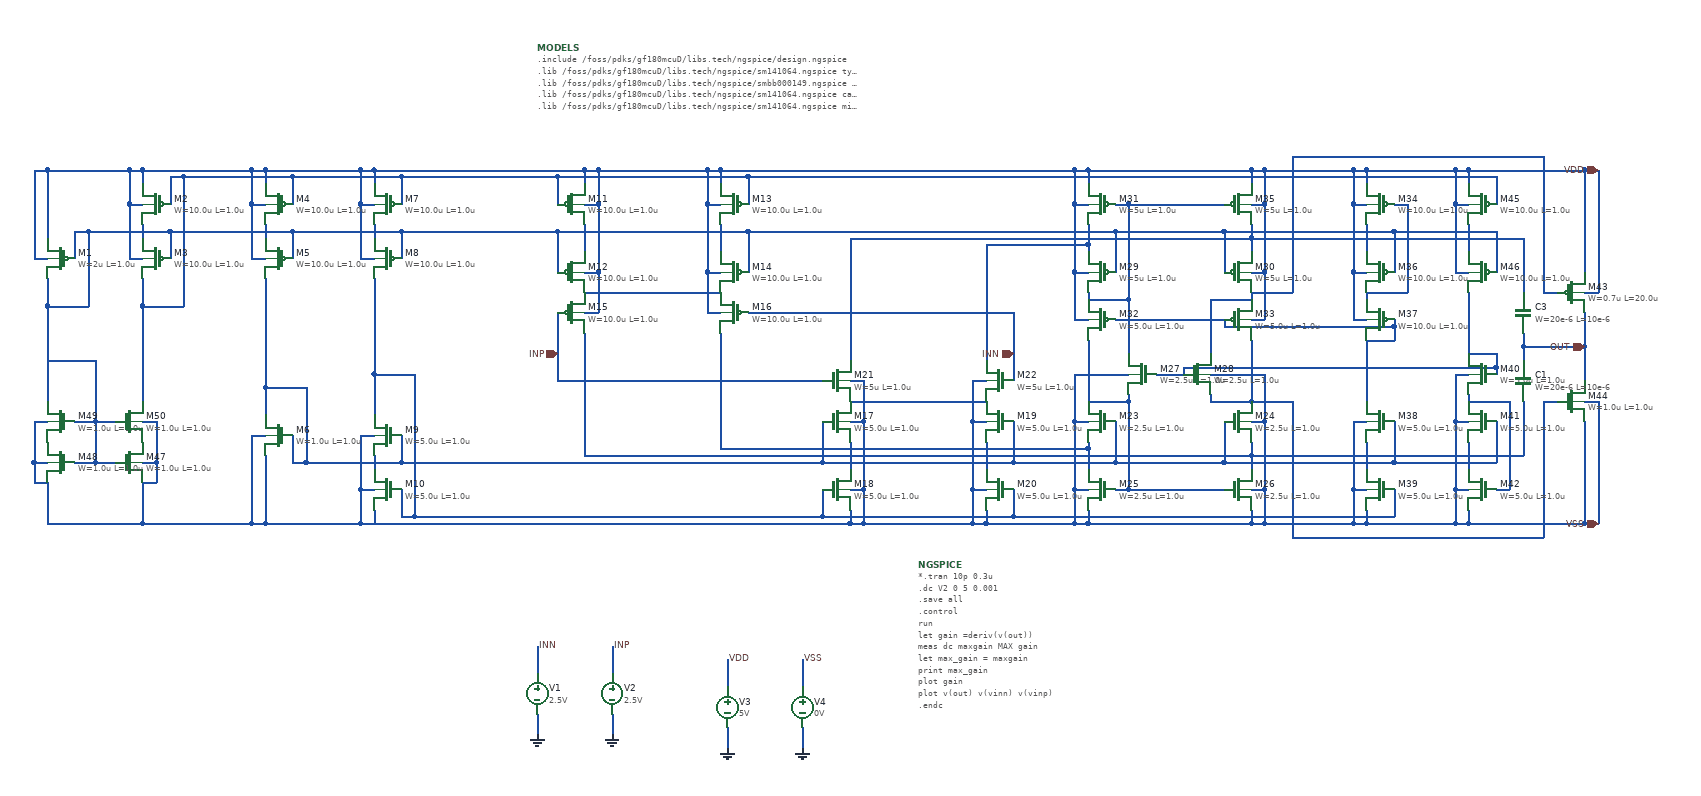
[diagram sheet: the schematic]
v {xschem version=3.4.8RC file_version=1.3}
G {}
K {}
V {}
S {}
F {}
E {}
P 4 1 -1230 -70 {}
N -1010 -230 -990 -230 {
lab=VDD}
N -830 -230 -810 -230 {
lab=VDD}
N -1010 -440 -1010 -420 {
lab=VDD}
N -1010 -390 -990 -390 {
lab=VDD}
N -1050 -430 -1050 -390 {
lab=#net1}
N -290 30 -290 80 {
lab=VSS}
N -290 30 -270 30 {
lab=VSS}
N -270 60 -270 80 {
lab=VSS}
N -270 -440 -270 -420 {
lab=VDD}
N -290 -390 -270 -390 {
lab=VDD}
N -30 -440 -30 -420 {
lab=VDD}
N -30 -390 -10 -390 {
lab=VDD}
N -10 -390 -10 -290 {
lab=VDD}
N -30 30 -10 30 {
lab=VSS}
N -30 60 -30 80 {
lab=VSS}
N -1050 -230 -1050 -130 {
lab=INP}
N -440 -130 -420 -130 {
lab=VSS}
N -620 -70 -600 -70 {
lab=VSS}
N -600 30 -600 80 {
lab=VSS}
N -620 30 -600 30 {
lab=VSS}
N -620 -40 -620 0 {
lab=#net2}
N -620 60 -620 80 {
lab=VSS}
N -660 30 -660 70 {
lab=#net3}
N -660 -70 -660 -10 {
lab=#net4}
N -1010 -290 -990 -290 {
lab=VDD}
N -1010 -360 -1010 -320 {
lab=#net5}
N -1050 -350 -1050 -290 {
lab=#net6}
N -290 -390 -290 -290 {
lab=VDD}
N -290 -290 -270 -290 {
lab=VDD}
N -270 -330 -270 -320 {
lab=#net7}
N -290 -70 -270 -70 {
lab=VSS}
N -290 -70 -290 30 {
lab=VSS}
N -270 -30 -270 0 {
lab=#net8}
N -30 -20 -30 0 {
lab=#net9}
N -30 -70 -10 -70 {
lab=VSS}
N -770 -230 -380 -230 {
lab=INN}
N -380 -230 -380 -130 {
lab=INN}
N -30 -290 -10 -290 {
lab=VDD}
N -30 -340 -30 -320 {
lab=#net10}
N -1010 -260 -810 -260 {
lab=#net11}
N -1050 -130 -660 -130 {
lab=INP}
N -620 -100 -420 -100 {
lab=#net12}
N -270 -260 -270 -250 {
lab=#net13}
N -290 -220 -270 -220 {
lab=VDD}
N -290 -290 -290 -220 {
lab=VDD}
N -210 30 -70 30 {
lab=#net14}
N -10 30 -10 80 {
lab=VSS}
N -170 -140 -130 -140 {
lab=#net15}
N -30 -220 -10 -220 {
lab=VDD}
N -10 -290 -10 -220 {
lab=VDD}
N -30 -260 -30 -250 {
lab=#net16}
N -90 -140 -10 -140 {
lab=VSS}
N -10 -140 -10 -70 {
lab=VSS}
N 460 -180 460 -130 {
lab=OUT}
N 460 -260 480 -260 {
lab=VDD}
N 480 -440 480 -260 {
lab=VDD}
N 140 -440 270 -440 {
lab=VDD}
N 460 -100 480 -100 {
lab=VSS}
N 480 -100 480 80 {
lab=VSS}
N 460 -70 460 80 {
lab=VSS}
N 460 -440 460 -290 {
lab=VDD}
N 120 -390 140 -390 {
lab=VDD}
N 120 -440 120 -390 {
lab=VDD}
N 140 -440 140 -420 {
lab=VDD}
N 140 -360 140 -320 {
lab=#net17}
N 120 -290 140 -290 {
lab=VDD}
N 120 -390 120 -290 {
lab=VDD}
N 140 -260 140 -250 {
lab=#net18}
N 120 -220 140 -220 {
lab=VDD}
N 120 -290 120 -220 {
lab=VDD}
N 120 -70 140 -70 {
lab=VSS}
N 120 30 120 80 {
lab=VSS}
N 120 30 140 30 {
lab=VSS}
N 140 -40 140 0 {
lab=#net19}
N 140 60 140 80 {
lab=VSS}
N 180 30 180 70 {
lab=#net3}
N 180 -70 180 -10 {
lab=#net4}
N 270 -390 290 -390 {
lab=VDD}
N 270 -440 270 -390 {
lab=VDD}
N 290 -440 290 -420 {
lab=VDD}
N 290 -360 290 -320 {
lab=#net20}
N 270 -290 290 -290 {
lab=VDD}
N 270 -390 270 -290 {
lab=VDD}
N 270 -70 290 -70 {
lab=VSS}
N 270 30 270 80 {
lab=VSS}
N 270 30 290 30 {
lab=VSS}
N 290 -40 290 0 {
lab=#net21}
N 290 60 290 80 {
lab=VSS}
N 290 -110 290 -100 {
lab=#net22}
N 270 -140 290 -140 {
lab=VSS}
N 270 -140 270 -70 {
lab=VSS}
N 290 -440 460 -440 {
lab=VDD}
N -810 -440 -810 -420 {
lab=VDD}
N -830 -390 -810 -390 {
lab=VDD}
N -770 -430 -770 -390 {
lab=#net1}
N -830 -290 -810 -290 {
lab=VDD}
N -810 -360 -810 -320 {
lab=#net23}
N -770 -350 -770 -290 {
lab=#net6}
N -440 -70 -420 -70 {
lab=VSS}
N -440 30 -420 30 {
lab=VSS}
N -420 -40 -420 0 {
lab=#net24}
N -420 60 -420 80 {
lab=VSS}
N -380 30 -380 70 {
lab=#net3}
N -380 -70 -380 -10 {
lab=#net4}
N -620 -130 -600 -130 {
lab=VSS}
N 180 -350 180 -290 {
lab=#net6}
N 180 -390 200 -390 {
lab=#net18}
N 200 -390 200 -260 {
lab=#net18}
N 140 -260 200 -260 {
lab=#net18}
N 180 -210 180 -190 {
lab=#net25}
N 140 -190 180 -190 {
lab=#net25}
N 140 -190 140 -100 {
lab=#net25}
N 330 -430 330 -390 {
lab=#net1}
N 330 -350 330 -290 {
lab=#net6}
N -70 -10 180 -10 {
lab=#net4}
N 330 -70 330 -10 {
lab=#net4}
N 330 30 350 30 {
lab=#net22}
N 350 -100 350 30 {
lab=#net22}
N 290 -100 350 -100 {
lab=#net22}
N 330 -150 330 -140 {
lab=#net15}
N 290 -170 330 -170 {
lab=#net15}
N 290 -260 290 -170 {
lab=#net15}
N -210 -390 -70 -390 {
lab=#net13}
N -230 -350 -230 -290 {
lab=#net6}
N -70 -350 -70 -290 {
lab=#net6}
N -230 -220 -70 -220 {
lab=#net25}
N -270 -190 -270 -100 {
lab=#net14}
N -210 -110 -210 -100 {
lab=#net14}
N -270 -100 -210 -100 {
lab=#net14}
N -90 -110 -90 -100 {
lab=#net26}
N -90 -100 -30 -100 {
lab=#net26}
N -290 -140 -210 -140 {
lab=VSS}
N -290 -140 -290 -70 {
lab=VSS}
N -30 -190 -30 -100 {
lab=#net26}
N -210 -250 -210 -170 {
lab=#net13}
N -270 -250 -210 -250 {
lab=#net13}
N -90 -250 -90 -170 {
lab=#net16}
N -90 -250 -30 -250 {
lab=#net16}
N 180 -350 330 -350 {
lab=#net6}
N -380 70 180 70 {
lab=#net3}
N 180 -10 330 -10 {
lab=#net4}
N -70 -210 180 -210 {
lab=#net25}
N -70 -220 -70 -210 {
lab=#net25}
N -130 -150 330 -150 {
lab=#net15}
N -130 -150 -130 -140 {
lab=#net15}
N -1010 -200 -1010 -20 {
lab=#net9}
N -810 -200 -810 -30 {
lab=#net8}
N -620 -340 -620 -160 {
lab=#net10}
N -420 -330 -420 -160 {
lab=#net7}
N -230 -70 -230 -10 {
lab=#net4}
N -70 -70 -70 -10 {
lab=#net4}
N -210 -100 -210 30 {
lab=#net14}
N -210 -390 -210 -250 {
lab=#net13}
N 460 -440 480 -440 {
lab=VDD}
N 400 -260 420 -260 {
lab=#net16}
N 400 -460 400 -260 {
lab=#net16}
N 30 -460 400 -460 {
lab=#net16}
N 30 -460 30 -260 {
lab=#net16}
N -30 -260 30 -260 {
lab=#net16}
N 400 -100 420 -100 {
lab=#net26}
N 400 -100 400 100 {
lab=#net26}
N 30 100 400 100 {
lab=#net26}
N 30 -100 30 100 {
lab=#net26}
N -30 -100 30 -100 {
lab=#net26}
N -30 -20 370 -20 {
lab=#net9}
N 370 -180 370 -160 {
lab=OUT}
N -620 -340 -30 -340 {
lab=#net10}
N -420 -330 -270 -330 {
lab=#net7}
N -810 -30 -270 -30 {
lab=#net8}
N -1010 -20 -30 -20 {
lab=#net9}
N -290 -440 -270 -440 {
lab=VDD}
N -30 -440 -10 -440 {
lab=VDD}
N 460 80 480 80 {
lab=VSS}
N -660 -10 -380 -10 {
lab=#net4}
N -660 70 -380 70 {
lab=#net3}
N -1050 -430 -770 -430 {
lab=#net1}
N -1050 -350 -770 -350 {
lab=#net6}
N -70 -350 180 -350 {
lab=#net6}
N -770 -430 330 -430 {
lab=#net1}
N -830 -440 -810 -440 {
lab=VDD}
N -1200 -430 -1050 -430 {
lab=#net1}
N -1200 -350 -1050 -350 {
lab=#net6}
N -1200 -10 -660 -10 {
lab=#net4}
N -1180 70 -660 70 {
lab=#net3}
N 370 -180 460 -180 {
lab=OUT}
N 370 -100 370 -20 {
lab=#net9}
N -30 -340 370 -340 {
lab=#net10}
N 370 -340 370 -260 {
lab=#net10}
N 370 -200 370 -180 {
lab=OUT}
N -830 -390 -830 -290 {
lab=VDD}
N -990 -390 -990 -290 {
lab=VDD}
N -440 30 -440 80 {
lab=VSS}
N -600 -130 -600 -70 {
lab=VSS}
N -440 -130 -440 -70 {
lab=VSS}
N -990 -290 -990 -230 {
lab=VDD}
N -830 -290 -830 -230 {
lab=VDD}
N -990 -440 -990 -390 {
lab=VDD}
N -420 80 -290 80 {
lab=VSS}
N -290 80 -270 80 {
lab=VSS}
N -290 -440 -290 -390 {
lab=VDD}
N -270 -440 -30 -440 {
lab=VDD}
N -10 -440 -10 -390 {
lab=VDD}
N -10 -70 -10 30 {
lab=VSS}
N -270 80 -30 80 {
lab=VSS}
N -620 80 -600 80 {
lab=VSS}
N -600 -70 -600 30 {
lab=VSS}
N -30 80 -10 80 {
lab=VSS}
N 290 80 460 80 {
lab=VSS}
N -10 -440 120 -440 {
lab=VDD}
N 120 -440 140 -440 {
lab=VDD}
N -10 80 120 80 {
lab=VSS}
N 120 -70 120 30 {
lab=VSS}
N 120 80 140 80 {
lab=VSS}
N 270 -440 290 -440 {
lab=VDD}
N 140 80 270 80 {
lab=VSS}
N 270 -70 270 30 {
lab=VSS}
N 270 80 290 80 {
lab=VSS}
N -830 -440 -830 -390 {
lab=VDD}
N -440 -70 -440 30 {
lab=VSS}
N -440 80 -420 80 {
lab=VSS}
N -770 -350 -230 -350 {
lab=#net6}
N -230 -350 -70 -350 {
lab=#net6}
N 180 -220 180 -210 {
lab=#net25}
N 330 -170 330 -150 {
lab=#net15}
N -380 -10 -230 -10 {
lab=#net4}
N -230 -10 -70 -10 {
lab=#net4}
N -230 30 -210 30 {
lab=#net14}
N -230 -390 -210 -390 {
lab=#net13}
N -30 -40 -30 -20 {
lab=#net9}
N -30 -360 -30 -340 {
lab=#net10}
N -270 -360 -270 -330 {
lab=#net7}
N -270 -40 -270 -30 {
lab=#net8}
N 460 -230 460 -180 {
lab=OUT}
N -600 80 -440 80 {
lab=VSS}
N -1010 -440 -990 -440 {
lab=VDD}
N -810 -440 -290 -440 {
lab=VDD}
N -990 -440 -830 -440 {
lab=VDD}
N -1340 -50 -1320 -50 {
lab=VSS}
N -1340 30 -1340 80 {
lab=VSS}
N -1340 30 -1320 30 {
lab=VSS}
N -1320 -20 -1320 0 {
lab=#net27}
N -1320 60 -1320 80 {
lab=VSS}
N -1320 -440 -1320 -420 {
lab=VDD}
N -1340 -390 -1320 -390 {
lab=VDD}
N -1340 -310 -1320 -310 {
lab=VDD}
N -1340 -390 -1340 -310 {
lab=VDD}
N -1320 -360 -1320 -340 {
lab=#net28}
N -1280 -350 -1280 -310 {
lab=#net6}
N -1280 -430 -1280 -390 {
lab=#net1}
N -1480 -440 -1480 -420 {
lab=VDD}
N -1500 -390 -1480 -390 {
lab=VDD}
N -1500 -310 -1480 -310 {
lab=VDD}
N -1500 -390 -1500 -310 {
lab=VDD}
N -1480 -360 -1480 -340 {
lab=#net29}
N -1440 -350 -1440 -310 {
lab=#net6}
N -1440 -430 -1440 -390 {
lab=#net1}
N -1500 -50 -1480 -50 {
lab=VSS}
N -1500 -50 -1500 80 {
lab=VSS}
N -1480 -20 -1480 80 {
lab=VSS}
N -1440 -50 -1440 -10 {
lab=#net4}
N -1440 -10 -1420 -10 {
lab=#net4}
N -1480 -120 -1420 -120 {
lab=#net4}
N -1280 -50 -1280 -10 {
lab=#net4}
N -1280 30 -1280 70 {
lab=#net3}
N -1280 70 -1260 70 {
lab=#net3}
N -1420 -10 -1280 -10 {
lab=#net4}
N -1320 -140 -1260 -140 {
lab=#net3}
N -1480 -280 -1480 -120 {
lab=#net4}
N -1320 -280 -1320 -140 {
lab=#net3}
N -1420 -120 -1420 -10 {
lab=#net4}
N -1260 -140 -1260 70 {
lab=#net3}
N -1320 -140 -1320 -80 {
lab=#net3}
N -1480 -120 -1480 -80 {
lab=#net4}
N -1280 -430 -1130 -430 {
lab=#net1}
N -1280 -350 -1130 -350 {
lab=#net6}
N -1660 80 -1500 80 {
lab=VSS}
N -1660 -440 -1660 -420 {
lab=VDD}
N -1680 -390 -1660 -390 {
lab=VDD}
N -1680 -310 -1660 -310 {
lab=VDD}
N -1680 -390 -1680 -310 {
lab=VDD}
N -1660 -360 -1660 -340 {
lab=#net30}
N -1620 -350 -1620 -310 {
lab=#net6}
N -1620 -430 -1620 -390 {
lab=#net1}
N -1660 -240 -1600 -240 {
lab=#net1}
N -1660 -240 -1660 -100 {
lab=#net1}
N -1800 -440 -1800 -340 {
lab=VDD}
N -1820 -310 -1800 -310 {
lab=VDD}
N -1820 -440 -1820 -310 {
lab=VDD}
N -1740 -350 -1620 -350 {
lab=#net6}
N -1760 -350 -1760 -310 {
lab=#net6}
N -1800 -240 -1740 -240 {
lab=#net6}
N -1800 -240 -1800 -100 {
lab=#net6}
N -1800 -280 -1800 -240 {
lab=#net6}
N -1660 -280 -1660 -240 {
lab=#net1}
N -1740 -350 -1740 -240 {
lab=#net6}
N -1600 -430 -1600 -240 {
lab=#net1}
N -1800 20 -1800 80 {
lab=VSS}
N -1660 20 -1660 80 {
lab=VSS}
N -1730 -10 -1700 -10 {
lab=#net6}
N -1820 -10 -1800 -10 {
lab=VSS}
N -1820 -10 -1820 20 {
lab=VSS}
N -1820 20 -1800 20 {
lab=VSS}
N -1660 -10 -1640 -10 {
lab=VSS}
N -1640 -10 -1640 20 {
lab=VSS}
N -1660 20 -1640 20 {
lab=VSS}
N -1730 -70 -1700 -70 {
lab=#net6}
N -1730 -70 -1730 -10 {
lab=#net6}
N -1820 -70 -1800 -70 {
lab=VSS}
N -1820 -70 -1820 -10 {
lab=VSS}
N -1660 -70 -1640 -70 {
lab=VSS}
N -1640 -70 -1640 -10 {
lab=VSS}
N -1730 -90 -1730 -70 {
lab=#net6}
N -1480 80 -1340 80 {
lab=VSS}
N -1340 -50 -1340 30 {
lab=VSS}
N -1340 80 -1320 80 {
lab=VSS}
N -1340 -440 -1320 -440 {
lab=VDD}
N -1340 -440 -1340 -390 {
lab=VDD}
N -1440 -350 -1280 -350 {
lab=#net6}
N -1440 -430 -1280 -430 {
lab=#net1}
N -1500 -440 -1480 -440 {
lab=VDD}
N -1500 -440 -1500 -390 {
lab=VDD}
N -1620 -350 -1440 -350 {
lab=#net6}
N -1600 -430 -1440 -430 {
lab=#net1}
N -1500 80 -1480 80 {
lab=VSS}
N -1680 -440 -1660 -440 {
lab=VDD}
N -1680 -440 -1680 -390 {
lab=VDD}
N -1820 -440 -1800 -440 {
lab=VDD}
N -1760 -350 -1740 -350 {
lab=#net6}
N -1620 -430 -1600 -430 {
lab=#net1}
N -1800 80 -1660 80 {
lab=VSS}
N -1760 -70 -1730 -70 {
lab=#net6}
N -1760 -10 -1730 -10 {
lab=#net6}
N -1480 -440 -1340 -440 {
lab=VDD}
N -1660 -440 -1500 -440 {
lab=VDD}
N -1800 -440 -1680 -440 {
lab=VDD}
N -1800 -160 -1730 -160 {lab=#net6}
N -1730 -160 -1730 -90 {lab=#net6}
N -1280 -10 -1140 -10 {lab=#net4}
N -1260 70 -1140 70 {lab=#net3}
N -1320 -440 -1010 -440 {lab=VDD}
N -1330 80 -620 80 {lab=VSS}
N -1080 360 -1080 390 {lab=GND}
N -1080 260 -1080 300 {lab=INN}
N -970 360 -970 390 {lab=GND}
N -970 260 -970 300 {lab=INP}
N -800 380 -800 410 {lab=GND}
N -800 280 -800 320 {lab=VDD}
N -690 380 -690 410 {lab=GND}
N -690 280 -690 320 {lab=VSS}
C {ipin.sym} -380 -170 2 0 {name=p1 lab=INN}
C {ipin.sym} -1050 -170 0 0 {name=p2 lab=INP}
C {iopin.sym} 480 -440 0 0 {name=p3 lab=VDD}
C {iopin.sym} 480 80 0 0 {name=p4 lab=VSS}
C {iopin.sym} 460 -180 0 0 {name=p5 lab=OUT}
C {symbols/pfet_06v0.sym} -1030 -390 0 0 {name=M11
L=1.0u
W=10.0u
nf=1
m=1
ad="'int((nf+1)/2) * W/nf * 0.18u'"
pd="'2*int((nf+1)/2) * (W/nf + 0.18u)'"
as="'int((nf+2)/2) * W/nf * 0.18u'"
ps="'2*int((nf+2)/2) * (W/nf + 0.18u)'"
nrd="'0.18u / W'" nrs="'0.18u / W'"
sa=0 sb=0 sd=0
model=pfet_06v0
spiceprefix=X
}
C {symbols/pfet_06v0.sym} -1030 -290 0 0 {name=M12
L=1.0u
W=10.0u
nf=1
m=1
ad="'int((nf+1)/2) * W/nf * 0.18u'"
pd="'2*int((nf+1)/2) * (W/nf + 0.18u)'"
as="'int((nf+2)/2) * W/nf * 0.18u'"
ps="'2*int((nf+2)/2) * (W/nf + 0.18u)'"
nrd="'0.18u / W'" nrs="'0.18u / W'"
sa=0 sb=0 sd=0
model=pfet_06v0
spiceprefix=X
}
C {symbols/pfet_06v0.sym} -790 -390 0 1 {name=M13
L=1.0u
W=10.0u
nf=1
m=1
ad="'int((nf+1)/2) * W/nf * 0.18u'"
pd="'2*int((nf+1)/2) * (W/nf + 0.18u)'"
as="'int((nf+2)/2) * W/nf * 0.18u'"
ps="'2*int((nf+2)/2) * (W/nf + 0.18u)'"
nrd="'0.18u / W'" nrs="'0.18u / W'"
sa=0 sb=0 sd=0
model=pfet_06v0
spiceprefix=X
}
C {symbols/pfet_06v0.sym} -790 -290 0 1 {name=M14
L=1.0u
W=10.0u
nf=1
m=1
ad="'int((nf+1)/2) * W/nf * 0.18u'"
pd="'2*int((nf+1)/2) * (W/nf + 0.18u)'"
as="'int((nf+2)/2) * W/nf * 0.18u'"
ps="'2*int((nf+2)/2) * (W/nf + 0.18u)'"
nrd="'0.18u / W'" nrs="'0.18u / W'"
sa=0 sb=0 sd=0
model=pfet_06v0
spiceprefix=X
}
C {symbols/pfet_06v0.sym} -1030 -230 0 0 {name=M15
L=1.0u
W=10.0u
nf=1
m=1
ad="'int((nf+1)/2) * W/nf * 0.18u'"
pd="'2*int((nf+1)/2) * (W/nf + 0.18u)'"
as="'int((nf+2)/2) * W/nf * 0.18u'"
ps="'2*int((nf+2)/2) * (W/nf + 0.18u)'"
nrd="'0.18u / W'" nrs="'0.18u / W'"
sa=0 sb=0 sd=0
model=pfet_06v0
spiceprefix=X
}
C {symbols/pfet_06v0.sym} -790 -230 0 1 {name=M16
L=1.0u
W=10.0u
nf=1
m=1
ad="'int((nf+1)/2) * W/nf * 0.18u'"
pd="'2*int((nf+1)/2) * (W/nf + 0.18u)'"
as="'int((nf+2)/2) * W/nf * 0.18u'"
ps="'2*int((nf+2)/2) * (W/nf + 0.18u)'"
nrd="'0.18u / W'" nrs="'0.18u / W'"
sa=0 sb=0 sd=0
model=pfet_06v0
spiceprefix=X
}
C {symbols/nfet_06v0.sym} -640 -70 0 0 {name=M17
L=1.0u
W=5.0u
nf=1
m=1
ad="'int((nf+1)/2) * W/nf * 0.18u'"
pd="'2*int((nf+1)/2) * (W/nf + 0.18u)'"
as="'int((nf+2)/2) * W/nf * 0.18u'"
ps="'2*int((nf+2)/2) * (W/nf + 0.18u)'"
nrd="'0.18u / W'" nrs="'0.18u / W'"
sa=0 sb=0 sd=0
model=nfet_06v0
spiceprefix=X
}
C {symbols/nfet_06v0.sym} -640 30 0 0 {name=M18
L=1.0u
W=5.0u
nf=1
m=1
ad="'int((nf+1)/2) * W/nf * 0.18u'"
pd="'2*int((nf+1)/2) * (W/nf + 0.18u)'"
as="'int((nf+2)/2) * W/nf * 0.18u'"
ps="'2*int((nf+2)/2) * (W/nf + 0.18u)'"
nrd="'0.18u / W'" nrs="'0.18u / W'"
sa=0 sb=0 sd=0
model=nfet_06v0
spiceprefix=X
}
C {symbols/nfet_06v0.sym} -400 -70 0 1 {name=M19
L=1.0u
W=5.0u
nf=1
m=1
ad="'int((nf+1)/2) * W/nf * 0.18u'"
pd="'2*int((nf+1)/2) * (W/nf + 0.18u)'"
as="'int((nf+2)/2) * W/nf * 0.18u'"
ps="'2*int((nf+2)/2) * (W/nf + 0.18u)'"
nrd="'0.18u / W'" nrs="'0.18u / W'"
sa=0 sb=0 sd=0
model=nfet_06v0
spiceprefix=X
}
C {symbols/nfet_06v0.sym} -400 30 0 1 {name=M20
L=1.0u
W=5.0u
nf=1
m=1
ad="'int((nf+1)/2) * W/nf * 0.18u'"
pd="'2*int((nf+1)/2) * (W/nf + 0.18u)'"
as="'int((nf+2)/2) * W/nf * 0.18u'"
ps="'2*int((nf+2)/2) * (W/nf + 0.18u)'"
nrd="'0.18u / W'" nrs="'0.18u / W'"
sa=0 sb=0 sd=0
model=nfet_06v0
spiceprefix=X
}
C {symbols/nfet_06v0.sym} -640 -130 0 0 {name=M21
L=1.0u
W=5u
nf=1
m=1
ad="'int((nf+1)/2) * W/nf * 0.18u'"
pd="'2*int((nf+1)/2) * (W/nf + 0.18u)'"
as="'int((nf+2)/2) * W/nf * 0.18u'"
ps="'2*int((nf+2)/2) * (W/nf + 0.18u)'"
nrd="'0.18u / W'" nrs="'0.18u / W'"
sa=0 sb=0 sd=0
model=nfet_06v0
spiceprefix=X
}
C {symbols/nfet_06v0.sym} -400 -130 0 1 {name=M22
L=1.0u
W=5u
nf=1
m=1
ad="'int((nf+1)/2) * W/nf * 0.18u'"
pd="'2*int((nf+1)/2) * (W/nf + 0.18u)'"
as="'int((nf+2)/2) * W/nf * 0.18u'"
ps="'2*int((nf+2)/2) * (W/nf + 0.18u)'"
nrd="'0.18u / W'" nrs="'0.18u / W'"
sa=0 sb=0 sd=0
model=nfet_06v0
spiceprefix=X
}
C {symbols/pfet_06v0.sym} -250 -290 0 1 {name=M29
L=1.0u
W=5u
nf=1
m=1
ad="'int((nf+1)/2) * W/nf * 0.18u'"
pd="'2*int((nf+1)/2) * (W/nf + 0.18u)'"
as="'int((nf+2)/2) * W/nf * 0.18u'"
ps="'2*int((nf+2)/2) * (W/nf + 0.18u)'"
nrd="'0.18u / W'" nrs="'0.18u / W'"
sa=0 sb=0 sd=0
model=pfet_06v0
spiceprefix=X
}
C {symbols/pfet_06v0.sym} -50 -290 0 0 {name=M30
L=1.0u
W=5u
nf=1
m=1
ad="'int((nf+1)/2) * W/nf * 0.18u'"
pd="'2*int((nf+1)/2) * (W/nf + 0.18u)'"
as="'int((nf+2)/2) * W/nf * 0.18u'"
ps="'2*int((nf+2)/2) * (W/nf + 0.18u)'"
nrd="'0.18u / W'" nrs="'0.18u / W'"
sa=0 sb=0 sd=0
model=pfet_06v0
spiceprefix=X
}
C {symbols/pfet_06v0.sym} -250 -390 0 1 {name=M31
L=1.0u
W=5u
nf=1
m=1
ad="'int((nf+1)/2) * W/nf * 0.18u'"
pd="'2*int((nf+1)/2) * (W/nf + 0.18u)'"
as="'int((nf+2)/2) * W/nf * 0.18u'"
ps="'2*int((nf+2)/2) * (W/nf + 0.18u)'"
nrd="'0.18u / W'" nrs="'0.18u / W'"
sa=0 sb=0 sd=0
model=pfet_06v0
spiceprefix=X
}
C {symbols/pfet_06v0.sym} -50 -390 0 0 {name=M35
L=1.0u
W=5u
nf=1
m=1
ad="'int((nf+1)/2) * W/nf * 0.18u'"
pd="'2*int((nf+1)/2) * (W/nf + 0.18u)'"
as="'int((nf+2)/2) * W/nf * 0.18u'"
ps="'2*int((nf+2)/2) * (W/nf + 0.18u)'"
nrd="'0.18u / W'" nrs="'0.18u / W'"
sa=0 sb=0 sd=0
model=pfet_06v0
spiceprefix=X
}
C {symbols/pfet_06v0.sym} -250 -220 0 1 {name=M32
L=1.0u
W=5.0u
nf=1
m=1
ad="'int((nf+1)/2) * W/nf * 0.18u'"
pd="'2*int((nf+1)/2) * (W/nf + 0.18u)'"
as="'int((nf+2)/2) * W/nf * 0.18u'"
ps="'2*int((nf+2)/2) * (W/nf + 0.18u)'"
nrd="'0.18u / W'" nrs="'0.18u / W'"
sa=0 sb=0 sd=0
model=pfet_06v0
spiceprefix=X
}
C {symbols/pfet_06v0.sym} -50 -220 0 0 {name=M33
L=1.0u
W=5.0u
nf=1
m=1
ad="'int((nf+1)/2) * W/nf * 0.18u'"
pd="'2*int((nf+1)/2) * (W/nf + 0.18u)'"
as="'int((nf+2)/2) * W/nf * 0.18u'"
ps="'2*int((nf+2)/2) * (W/nf + 0.18u)'"
nrd="'0.18u / W'" nrs="'0.18u / W'"
sa=0 sb=0 sd=0
model=pfet_06v0
spiceprefix=X
}
C {symbols/nfet_06v0.sym} -250 -70 0 1 {name=M23
L=1.0u
W=2.5u
nf=1
m=1
ad="'int((nf+1)/2) * W/nf * 0.18u'"
pd="'2*int((nf+1)/2) * (W/nf + 0.18u)'"
as="'int((nf+2)/2) * W/nf * 0.18u'"
ps="'2*int((nf+2)/2) * (W/nf + 0.18u)'"
nrd="'0.18u / W'" nrs="'0.18u / W'"
sa=0 sb=0 sd=0
model=nfet_06v0
spiceprefix=X
}
C {symbols/nfet_06v0.sym} -50 -70 0 0 {name=M24
L=1.0u
W=2.5u
nf=1
m=1
ad="'int((nf+1)/2) * W/nf * 0.18u'"
pd="'2*int((nf+1)/2) * (W/nf + 0.18u)'"
as="'int((nf+2)/2) * W/nf * 0.18u'"
ps="'2*int((nf+2)/2) * (W/nf + 0.18u)'"
nrd="'0.18u / W'" nrs="'0.18u / W'"
sa=0 sb=0 sd=0
model=nfet_06v0
spiceprefix=X
}
C {symbols/nfet_06v0.sym} -250 30 0 1 {name=M25
L=1.0u
W=2.5u
nf=1
m=1
ad="'int((nf+1)/2) * W/nf * 0.18u'"
pd="'2*int((nf+1)/2) * (W/nf + 0.18u)'"
as="'int((nf+2)/2) * W/nf * 0.18u'"
ps="'2*int((nf+2)/2) * (W/nf + 0.18u)'"
nrd="'0.18u / W'" nrs="'0.18u / W'"
sa=0 sb=0 sd=0
model=nfet_06v0
spiceprefix=X
}
C {symbols/nfet_06v0.sym} -50 30 0 0 {name=M26
L=1.0u
W=2.5u
nf=1
m=1
ad="'int((nf+1)/2) * W/nf * 0.18u'"
pd="'2*int((nf+1)/2) * (W/nf + 0.18u)'"
as="'int((nf+2)/2) * W/nf * 0.18u'"
ps="'2*int((nf+2)/2) * (W/nf + 0.18u)'"
nrd="'0.18u / W'" nrs="'0.18u / W'"
sa=0 sb=0 sd=0
model=nfet_06v0
spiceprefix=X
}
C {symbols/nfet_06v0.sym} -190 -140 0 1 {name=M27
L=1.0u
W=2.5u
nf=1
m=1
ad="'int((nf+1)/2) * W/nf * 0.18u'"
pd="'2*int((nf+1)/2) * (W/nf + 0.18u)'"
as="'int((nf+2)/2) * W/nf * 0.18u'"
ps="'2*int((nf+2)/2) * (W/nf + 0.18u)'"
nrd="'0.18u / W'" nrs="'0.18u / W'"
sa=0 sb=0 sd=0
model=nfet_06v0
spiceprefix=X
}
C {symbols/nfet_06v0.sym} -110 -140 0 0 {name=M28
L=1.0u
W=2.5u
nf=1
m=1
ad="'int((nf+1)/2) * W/nf * 0.18u'"
pd="'2*int((nf+1)/2) * (W/nf + 0.18u)'"
as="'int((nf+2)/2) * W/nf * 0.18u'"
ps="'2*int((nf+2)/2) * (W/nf + 0.18u)'"
nrd="'0.18u / W'" nrs="'0.18u / W'"
sa=0 sb=0 sd=0
model=nfet_06v0
spiceprefix=X
}
C {symbols/pfet_06v0.sym} 160 -390 0 1 {name=M34
L=1.0u
W=10.0u
nf=1
m=1
ad="'int((nf+1)/2) * W/nf * 0.18u'"
pd="'2*int((nf+1)/2) * (W/nf + 0.18u)'"
as="'int((nf+2)/2) * W/nf * 0.18u'"
ps="'2*int((nf+2)/2) * (W/nf + 0.18u)'"
nrd="'0.18u / W'" nrs="'0.18u / W'"
sa=0 sb=0 sd=0
model=pfet_06v0
spiceprefix=X
}
C {symbols/pfet_06v0.sym} 160 -290 0 1 {name=M36
L=1.0u
W=10.0u
nf=1
m=1
ad="'int((nf+1)/2) * W/nf * 0.18u'"
pd="'2*int((nf+1)/2) * (W/nf + 0.18u)'"
as="'int((nf+2)/2) * W/nf * 0.18u'"
ps="'2*int((nf+2)/2) * (W/nf + 0.18u)'"
nrd="'0.18u / W'" nrs="'0.18u / W'"
sa=0 sb=0 sd=0
model=pfet_06v0
spiceprefix=X
}
C {symbols/pfet_06v0.sym} 160 -220 0 1 {name=M37
L=1.0u
W=10.0u
nf=1
m=1
ad="'int((nf+1)/2) * W/nf * 0.18u'"
pd="'2*int((nf+1)/2) * (W/nf + 0.18u)'"
as="'int((nf+2)/2) * W/nf * 0.18u'"
ps="'2*int((nf+2)/2) * (W/nf + 0.18u)'"
nrd="'0.18u / W'" nrs="'0.18u / W'"
sa=0 sb=0 sd=0
model=pfet_06v0
spiceprefix=X
}
C {symbols/nfet_06v0.sym} 160 -70 0 1 {name=M38
L=1.0u
W=5.0u
nf=1
m=1
ad="'int((nf+1)/2) * W/nf * 0.18u'"
pd="'2*int((nf+1)/2) * (W/nf + 0.18u)'"
as="'int((nf+2)/2) * W/nf * 0.18u'"
ps="'2*int((nf+2)/2) * (W/nf + 0.18u)'"
nrd="'0.18u / W'" nrs="'0.18u / W'"
sa=0 sb=0 sd=0
model=nfet_06v0
spiceprefix=X
}
C {symbols/nfet_06v0.sym} 160 30 0 1 {name=M39
L=1.0u
W=5.0u
nf=1
m=1
ad="'int((nf+1)/2) * W/nf * 0.18u'"
pd="'2*int((nf+1)/2) * (W/nf + 0.18u)'"
as="'int((nf+2)/2) * W/nf * 0.18u'"
ps="'2*int((nf+2)/2) * (W/nf + 0.18u)'"
nrd="'0.18u / W'" nrs="'0.18u / W'"
sa=0 sb=0 sd=0
model=nfet_06v0
spiceprefix=X
}
C {symbols/pfet_06v0.sym} 310 -390 0 1 {name=M45
L=1.0u
W=10.0u
nf=1
m=1
ad="'int((nf+1)/2) * W/nf * 0.18u'"
pd="'2*int((nf+1)/2) * (W/nf + 0.18u)'"
as="'int((nf+2)/2) * W/nf * 0.18u'"
ps="'2*int((nf+2)/2) * (W/nf + 0.18u)'"
nrd="'0.18u / W'" nrs="'0.18u / W'"
sa=0 sb=0 sd=0
model=pfet_06v0
spiceprefix=X
}
C {symbols/pfet_06v0.sym} 310 -290 0 1 {name=M46
L=1.0u
W=10.0u
nf=1
m=1
ad="'int((nf+1)/2) * W/nf * 0.18u'"
pd="'2*int((nf+1)/2) * (W/nf + 0.18u)'"
as="'int((nf+2)/2) * W/nf * 0.18u'"
ps="'2*int((nf+2)/2) * (W/nf + 0.18u)'"
nrd="'0.18u / W'" nrs="'0.18u / W'"
sa=0 sb=0 sd=0
model=pfet_06v0
spiceprefix=X
}
C {symbols/nfet_06v0.sym} 310 -140 0 1 {name=M40
L=1.0u
W=5.0u
nf=1
m=1
ad="'int((nf+1)/2) * W/nf * 0.18u'"
pd="'2*int((nf+1)/2) * (W/nf + 0.18u)'"
as="'int((nf+2)/2) * W/nf * 0.18u'"
ps="'2*int((nf+2)/2) * (W/nf + 0.18u)'"
nrd="'0.18u / W'" nrs="'0.18u / W'"
sa=0 sb=0 sd=0
model=nfet_06v0
spiceprefix=X
}
C {symbols/nfet_06v0.sym} 310 -70 0 1 {name=M41
L=1.0u
W=5.0u
nf=1
m=1
ad="'int((nf+1)/2) * W/nf * 0.18u'"
pd="'2*int((nf+1)/2) * (W/nf + 0.18u)'"
as="'int((nf+2)/2) * W/nf * 0.18u'"
ps="'2*int((nf+2)/2) * (W/nf + 0.18u)'"
nrd="'0.18u / W'" nrs="'0.18u / W'"
sa=0 sb=0 sd=0
model=nfet_06v0
spiceprefix=X
}
C {symbols/nfet_06v0.sym} 310 30 0 1 {name=M42
L=1.0u
W=5.0u
nf=1
m=1
ad="'int((nf+1)/2) * W/nf * 0.18u'"
pd="'2*int((nf+1)/2) * (W/nf + 0.18u)'"
as="'int((nf+2)/2) * W/nf * 0.18u'"
ps="'2*int((nf+2)/2) * (W/nf + 0.18u)'"
nrd="'0.18u / W'" nrs="'0.18u / W'"
sa=0 sb=0 sd=0
model=nfet_06v0
spiceprefix=X
}
C {symbols/pfet_06v0.sym} 440 -260 0 0 {name=M43
L=20.0u
W=0.7u
nf=1
m=1
ad="'int((nf+1)/2) * W/nf * 0.18u'"
pd="'2*int((nf+1)/2) * (W/nf + 0.18u)'"
as="'int((nf+2)/2) * W/nf * 0.18u'"
ps="'2*int((nf+2)/2) * (W/nf + 0.18u)'"
nrd="'0.18u / W'" nrs="'0.18u / W'"
sa=0 sb=0 sd=0
model=pfet_06v0
spiceprefix=X
}
C {symbols/nfet_06v0.sym} 440 -100 0 0 {name=M44
L=1.0u
W=1.0u
nf=1
m=1
ad="'int((nf+1)/2) * W/nf * 0.18u'"
pd="'2*int((nf+1)/2) * (W/nf + 0.18u)'"
as="'int((nf+2)/2) * W/nf * 0.18u'"
ps="'2*int((nf+2)/2) * (W/nf + 0.18u)'"
nrd="'0.18u / W'" nrs="'0.18u / W'"
sa=0 sb=0 sd=0
model=nfet_06v0
spiceprefix=X
}
C {symbols/cap_mim_2f0fF.sym} 370 -230 0 0 {name=C3
W=20e-6
L=10e-6
model=cap_mim_2f0fF
spiceprefix=X
m=1}
C {symbols/cap_mim_2f0fF.sym} 370 -130 0 0 {name=C1
W=20e-6
L=10e-6
model=cap_mim_2f0fF
spiceprefix=X
m=1}
C {symbols/pfet_06v0.sym} -1460 -390 0 1 {name=M4
L=1.0u
W=10.0u
nf=1
m=1
ad="'int((nf+1)/2) * W/nf * 0.18u'"
pd="'2*int((nf+1)/2) * (W/nf + 0.18u)'"
as="'int((nf+2)/2) * W/nf * 0.18u'"
ps="'2*int((nf+2)/2) * (W/nf + 0.18u)'"
nrd="'0.18u / W'" nrs="'0.18u / W'"
sa=0 sb=0 sd=0
model=pfet_06v0
spiceprefix=X
}
C {symbols/pfet_06v0.sym} -1460 -310 0 1 {name=M5
L=1.0u
W=10.0u
nf=1
m=1
ad="'int((nf+1)/2) * W/nf * 0.18u'"
pd="'2*int((nf+1)/2) * (W/nf + 0.18u)'"
as="'int((nf+2)/2) * W/nf * 0.18u'"
ps="'2*int((nf+2)/2) * (W/nf + 0.18u)'"
nrd="'0.18u / W'" nrs="'0.18u / W'"
sa=0 sb=0 sd=0
model=pfet_06v0
spiceprefix=X
}
C {symbols/nfet_06v0.sym} -1460 -50 0 1 {name=M6
L=1.0u
W=1.0u
nf=1
m=1
ad="'int((nf+1)/2) * W/nf * 0.18u'"
pd="'2*int((nf+1)/2) * (W/nf + 0.18u)'"
as="'int((nf+2)/2) * W/nf * 0.18u'"
ps="'2*int((nf+2)/2) * (W/nf + 0.18u)'"
nrd="'0.18u / W'" nrs="'0.18u / W'"
sa=0 sb=0 sd=0
model=nfet_06v0
spiceprefix=X
}
C {symbols/pfet_06v0.sym} -1300 -390 0 1 {name=M7
L=1.0u
W=10.0u
nf=1
m=1
ad="'int((nf+1)/2) * W/nf * 0.18u'"
pd="'2*int((nf+1)/2) * (W/nf + 0.18u)'"
as="'int((nf+2)/2) * W/nf * 0.18u'"
ps="'2*int((nf+2)/2) * (W/nf + 0.18u)'"
nrd="'0.18u / W'" nrs="'0.18u / W'"
sa=0 sb=0 sd=0
model=pfet_06v0
spiceprefix=X
}
C {symbols/pfet_06v0.sym} -1300 -310 0 1 {name=M8
L=1.0u
W=10.0u
nf=1
m=1
ad="'int((nf+1)/2) * W/nf * 0.18u'"
pd="'2*int((nf+1)/2) * (W/nf + 0.18u)'"
as="'int((nf+2)/2) * W/nf * 0.18u'"
ps="'2*int((nf+2)/2) * (W/nf + 0.18u)'"
nrd="'0.18u / W'" nrs="'0.18u / W'"
sa=0 sb=0 sd=0
model=pfet_06v0
spiceprefix=X
}
C {symbols/nfet_06v0.sym} -1300 -50 0 1 {name=M9
L=1.0u
W=5.0u
nf=1
m=1
ad="'int((nf+1)/2) * W/nf * 0.18u'"
pd="'2*int((nf+1)/2) * (W/nf + 0.18u)'"
as="'int((nf+2)/2) * W/nf * 0.18u'"
ps="'2*int((nf+2)/2) * (W/nf + 0.18u)'"
nrd="'0.18u / W'" nrs="'0.18u / W'"
sa=0 sb=0 sd=0
model=nfet_06v0
spiceprefix=X
}
C {symbols/nfet_06v0.sym} -1300 30 0 1 {name=M10
L=1.0u
W=5.0u
nf=1
m=1
ad="'int((nf+1)/2) * W/nf * 0.18u'"
pd="'2*int((nf+1)/2) * (W/nf + 0.18u)'"
as="'int((nf+2)/2) * W/nf * 0.18u'"
ps="'2*int((nf+2)/2) * (W/nf + 0.18u)'"
nrd="'0.18u / W'" nrs="'0.18u / W'"
sa=0 sb=0 sd=0
model=nfet_06v0
spiceprefix=X
}
C {symbols/pfet_06v0.sym} -1780 -310 0 1 {name=M1
L=1.0u
W=2u
nf=1
m=1
ad="'int((nf+1)/2) * W/nf * 0.18u'"
pd="'2*int((nf+1)/2) * (W/nf + 0.18u)'"
as="'int((nf+2)/2) * W/nf * 0.18u'"
ps="'2*int((nf+2)/2) * (W/nf + 0.18u)'"
nrd="'0.18u / W'" nrs="'0.18u / W'"
sa=0 sb=0 sd=0
model=pfet_06v0
spiceprefix=X
}
C {symbols/pfet_06v0.sym} -1640 -390 0 1 {name=M2
L=1.0u
W=10.0u
nf=1
m=1
ad="'int((nf+1)/2) * W/nf * 0.18u'"
pd="'2*int((nf+1)/2) * (W/nf + 0.18u)'"
as="'int((nf+2)/2) * W/nf * 0.18u'"
ps="'2*int((nf+2)/2) * (W/nf + 0.18u)'"
nrd="'0.18u / W'" nrs="'0.18u / W'"
sa=0 sb=0 sd=0
model=pfet_06v0
spiceprefix=X
}
C {symbols/pfet_06v0.sym} -1640 -310 0 1 {name=M3
L=1.0u
W=10.0u
nf=1
m=1
ad="'int((nf+1)/2) * W/nf * 0.18u'"
pd="'2*int((nf+1)/2) * (W/nf + 0.18u)'"
as="'int((nf+2)/2) * W/nf * 0.18u'"
ps="'2*int((nf+2)/2) * (W/nf + 0.18u)'"
nrd="'0.18u / W'" nrs="'0.18u / W'"
sa=0 sb=0 sd=0
model=pfet_06v0
spiceprefix=X
}
C {symbols/nfet_06v0.sym} -1680 -10 0 0 {name=M47
L=1.0u
W=1.0u
nf=1
m=1
ad="'int((nf+1)/2) * W/nf * 0.18u'"
pd="'2*int((nf+1)/2) * (W/nf + 0.18u)'"
as="'int((nf+2)/2) * W/nf * 0.18u'"
ps="'2*int((nf+2)/2) * (W/nf + 0.18u)'"
nrd="'0.18u / W'" nrs="'0.18u / W'"
sa=0 sb=0 sd=0
model=nfet_06v0
spiceprefix=X
}
C {symbols/nfet_06v0.sym} -1780 -10 0 1 {name=M48
L=1.0u
W=1.0u
nf=1
m=1
ad="'int((nf+1)/2) * W/nf * 0.18u'"
pd="'2*int((nf+1)/2) * (W/nf + 0.18u)'"
as="'int((nf+2)/2) * W/nf * 0.18u'"
ps="'2*int((nf+2)/2) * (W/nf + 0.18u)'"
nrd="'0.18u / W'" nrs="'0.18u / W'"
sa=0 sb=0 sd=0
model=nfet_06v0
spiceprefix=X
}
C {symbols/nfet_06v0.sym} -1780 -70 0 1 {name=M49
L=1.0u
W=1.0u
nf=1
m=1
ad="'int((nf+1)/2) * W/nf * 0.18u'"
pd="'2*int((nf+1)/2) * (W/nf + 0.18u)'"
as="'int((nf+2)/2) * W/nf * 0.18u'"
ps="'2*int((nf+2)/2) * (W/nf + 0.18u)'"
nrd="'0.18u / W'" nrs="'0.18u / W'"
sa=0 sb=0 sd=0
model=nfet_06v0
spiceprefix=X
}
C {symbols/nfet_06v0.sym} -1680 -70 0 0 {name=M50
L=1.0u
W=1.0u
nf=1
m=1
ad="'int((nf+1)/2) * W/nf * 0.18u'"
pd="'2*int((nf+1)/2) * (W/nf + 0.18u)'"
as="'int((nf+2)/2) * W/nf * 0.18u'"
ps="'2*int((nf+2)/2) * (W/nf + 0.18u)'"
nrd="'0.18u / W'" nrs="'0.18u / W'"
sa=0 sb=0 sd=0
model=nfet_06v0
spiceprefix=X
}
C {code_shown.sym} -520 140 0 0 {name=NGSPICE only_toplevel=false value="
*.tran 10p 0.3u
.dc V2 0 5 0.001 
.save all
.control
run
let gain =deriv(v(out))
meas dc maxgain MAX gain
let max_gain = maxgain
print max_gain
plot gain
plot v(out) v(vinn) v(vinp)

.endc"

}
C {code_shown.sym} -1080 -620 0 0 {name=MODELS only_toplevel=false value=".include /foss/pdks/gf180mcuD/libs.tech/ngspice/design.ngspice
.lib /foss/pdks/gf180mcuD/libs.tech/ngspice/sm141064.ngspice typical
.lib /foss/pdks/gf180mcuD/libs.tech/ngspice/smbb000149.ngspice typical
.lib /foss/pdks/gf180mcuD/libs.tech/ngspice/sm141064.ngspice cap_mim
.lib /foss/pdks/gf180mcuD/libs.tech/ngspice/sm141064.ngspice mimcap_typical"}
C {vsource.sym} -1080 330 0 0 {name=V1 value=2.5V savecurrent=false}
C {gnd.sym} -1080 390 0 0 {name=l6 lab=GND}
C {vsource.sym} -970 330 0 0 {name=V2 value=2.5V savecurrent=false}
C {gnd.sym} -970 390 0 0 {name=l5 lab=GND}
C {lab_pin.sym} -970 260 2 0 {name=p11 sig_type=std_logic lab=INP}
C {lab_pin.sym} -1080 260 2 0 {name=p6 sig_type=std_logic lab=INN
}
C {vsource.sym} -800 350 0 0 {name=V3 value=5V savecurrent=false}
C {gnd.sym} -800 410 0 0 {name=l1 lab=GND}
C {lab_pin.sym} -800 280 2 0 {name=p7 sig_type=std_logic lab=VDD}
C {vsource.sym} -690 350 0 0 {name=V4 value=0V savecurrent=false}
C {gnd.sym} -690 410 0 0 {name=l2 lab=GND}
C {lab_pin.sym} -690 280 2 0 {name=p8 sig_type=std_logic lab=VSS}
